VERSION 5.7 ;
  NOWIREEXTENSIONATPIN ON ;
  DIVIDERCHAR "/" ;
  BUSBITCHARS "[]" ;
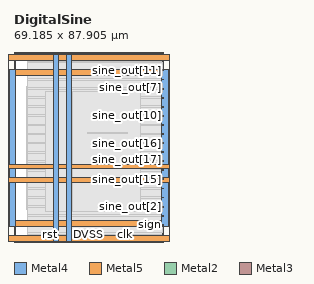
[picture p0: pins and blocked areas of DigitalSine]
MACRO DigitalSine
  CLASS BLOCK ;
  FOREIGN DigitalSine ;
  ORIGIN 0.000 0.000 ;
  SIZE 69.185 BY 87.905 ;
  PIN DVDD
    DIRECTION INOUT ;
    USE POWER ;
    PORT
      LAYER Metal4 ;
        RECT -2.240 7.120 0.760 79.820 ;
    END
    PORT
      LAYER Metal4 ;
        RECT 68.360 7.120 71.360 79.820 ;
    END
    PORT
      LAYER Metal5 ;
        RECT -2.240 7.120 71.360 10.120 ;
    END
    PORT
      LAYER Metal5 ;
        RECT -2.240 76.820 71.360 79.820 ;
    END
    PORT
      LAYER Metal4 ;
        RECT 18.260 0.120 20.460 86.820 ;
    END
    PORT
      LAYER Metal5 ;
        RECT -9.240 27.620 78.360 29.820 ;
    END
  END DVDD
  PIN DVSS
    DIRECTION INOUT ;
    USE GROUND ;
    PORT
      LAYER Metal4 ;
        RECT -9.240 0.120 -6.240 86.820 ;
    END
    PORT
      LAYER Metal4 ;
        RECT 75.360 0.120 78.360 86.820 ;
    END
    PORT
      LAYER Metal5 ;
        RECT -9.240 0.120 78.360 3.120 ;
    END
    PORT
      LAYER Metal5 ;
        RECT -9.240 83.820 78.360 86.820 ;
    END
    PORT
      LAYER Metal4 ;
        RECT 24.460 0.120 26.660 86.820 ;
    END
    PORT
      LAYER Metal5 ;
        RECT -9.240 33.820 78.360 36.020 ;
    END
  END DVSS
  PIN clk
    DIRECTION INPUT ;
    USE SIGNAL ;
    ANTENNAGATEAREA 1.450800 ;
    PORT
      LAYER Metal2 ;
        RECT 51.160 0.000 51.560 0.400 ;
    END
  END clk
  PIN rst
    DIRECTION INPUT ;
    USE SIGNAL ;
    ANTENNAGATEAREA 0.180700 ;
    PORT
      LAYER Metal2 ;
        RECT 16.600 0.000 17.000 0.400 ;
    END
  END rst
  PIN sign
    DIRECTION OUTPUT ;
    USE SIGNAL ;
    ANTENNADIFFAREA 0.708600 ;
    PORT
      LAYER Metal3 ;
        RECT 68.785 7.780 69.185 8.180 ;
    END
  END sign
  PIN signB
    DIRECTION OUTPUT ;
    USE SIGNAL ;
    ANTENNADIFFAREA 0.708600 ;
    PORT
      LAYER Metal3 ;
        RECT 68.785 3.580 69.185 3.980 ;
    END
  END signB
  PIN sine_out[0]
    DIRECTION OUTPUT ;
    USE SIGNAL ;
    ANTENNADIFFAREA 0.708600 ;
    PORT
      LAYER Metal3 ;
        RECT 68.785 11.980 69.185 12.380 ;
    END
  END sine_out[0]
  PIN sine_out[10]
    DIRECTION OUTPUT ;
    USE SIGNAL ;
    ANTENNADIFFAREA 0.708600 ;
    PORT
      LAYER Metal3 ;
        RECT 68.785 58.180 69.185 58.580 ;
    END
  END sine_out[10]
  PIN sine_out[11]
    DIRECTION OUTPUT ;
    USE SIGNAL ;
    ANTENNADIFFAREA 0.708600 ;
    PORT
      LAYER Metal3 ;
        RECT 68.785 79.180 69.185 79.580 ;
    END
  END sine_out[11]
  PIN sine_out[12]
    DIRECTION OUTPUT ;
    USE SIGNAL ;
    ANTENNADIFFAREA 0.708600 ;
    PORT
      LAYER Metal3 ;
        RECT 68.785 62.380 69.185 62.780 ;
    END
  END sine_out[12]
  PIN sine_out[13]
    DIRECTION OUTPUT ;
    USE SIGNAL ;
    ANTENNADIFFAREA 0.708600 ;
    PORT
      LAYER Metal3 ;
        RECT 68.785 70.780 69.185 71.180 ;
    END
  END sine_out[13]
  PIN sine_out[14]
    DIRECTION OUTPUT ;
    USE SIGNAL ;
    ANTENNADIFFAREA 0.708600 ;
    PORT
      LAYER Metal3 ;
        RECT 68.785 53.980 69.185 54.380 ;
    END
  END sine_out[14]
  PIN sine_out[15]
    DIRECTION OUTPUT ;
    USE SIGNAL ;
    ANTENNADIFFAREA 0.708600 ;
    PORT
      LAYER Metal3 ;
        RECT 68.785 28.780 69.185 29.180 ;
    END
  END sine_out[15]
  PIN sine_out[16]
    DIRECTION OUTPUT ;
    USE SIGNAL ;
    ANTENNADIFFAREA 0.708600 ;
    PORT
      LAYER Metal3 ;
        RECT 68.785 45.580 69.185 45.980 ;
    END
  END sine_out[16]
  PIN sine_out[17]
    DIRECTION OUTPUT ;
    USE SIGNAL ;
    ANTENNADIFFAREA 0.708600 ;
    PORT
      LAYER Metal3 ;
        RECT 68.785 41.380 69.185 41.780 ;
    END
  END sine_out[17]
  PIN sine_out[1]
    DIRECTION OUTPUT ;
    USE SIGNAL ;
    ANTENNADIFFAREA 0.708600 ;
    PORT
      LAYER Metal3 ;
        RECT 68.785 20.380 69.185 20.780 ;
    END
  END sine_out[1]
  PIN sine_out[2]
    DIRECTION OUTPUT ;
    USE SIGNAL ;
    ANTENNADIFFAREA 0.708600 ;
    PORT
      LAYER Metal3 ;
        RECT 68.785 16.180 69.185 16.580 ;
    END
  END sine_out[2]
  PIN sine_out[3]
    DIRECTION OUTPUT ;
    USE SIGNAL ;
    ANTENNADIFFAREA 0.708600 ;
    PORT
      LAYER Metal3 ;
        RECT 68.785 37.180 69.185 37.580 ;
    END
  END sine_out[3]
  PIN sine_out[4]
    DIRECTION OUTPUT ;
    USE SIGNAL ;
    ANTENNADIFFAREA 0.708600 ;
    PORT
      LAYER Metal3 ;
        RECT 68.785 24.580 69.185 24.980 ;
    END
  END sine_out[4]
  PIN sine_out[5]
    DIRECTION OUTPUT ;
    USE SIGNAL ;
    ANTENNADIFFAREA 0.708600 ;
    PORT
      LAYER Metal3 ;
        RECT 68.785 49.780 69.185 50.180 ;
    END
  END sine_out[5]
  PIN sine_out[6]
    DIRECTION OUTPUT ;
    USE SIGNAL ;
    ANTENNADIFFAREA 0.708600 ;
    PORT
      LAYER Metal3 ;
        RECT 68.785 32.980 69.185 33.380 ;
    END
  END sine_out[6]
  PIN sine_out[7]
    DIRECTION OUTPUT ;
    USE SIGNAL ;
    ANTENNADIFFAREA 0.708600 ;
    PORT
      LAYER Metal3 ;
        RECT 68.785 74.980 69.185 75.380 ;
    END
  END sine_out[7]
  PIN sine_out[8]
    DIRECTION OUTPUT ;
    USE SIGNAL ;
    ANTENNADIFFAREA 0.708600 ;
    PORT
      LAYER Metal3 ;
        RECT 68.785 66.580 69.185 66.980 ;
    END
  END sine_out[8]
  PIN sine_out[9]
    DIRECTION OUTPUT ;
    USE SIGNAL ;
    ANTENNADIFFAREA 0.708600 ;
    PORT
      LAYER Metal3 ;
        RECT 68.785 83.380 69.185 83.780 ;
    END
  END sine_out[9]
  OBS
      LAYER GatPoly ;
        RECT 5.760 14.970 63.360 71.970 ;
      LAYER Metal1 ;
        RECT 5.760 14.900 63.360 72.040 ;
      LAYER Metal2 ;
        RECT 6.135 0.610 64.425 83.725 ;
        RECT 6.135 0.400 16.390 0.610 ;
        RECT 17.210 0.400 50.950 0.610 ;
        RECT 51.770 0.400 64.425 0.610 ;
      LAYER Metal3 ;
        RECT 6.095 83.170 68.575 83.680 ;
        RECT 6.095 79.790 68.785 83.170 ;
        RECT 6.095 78.970 68.575 79.790 ;
        RECT 6.095 75.590 68.785 78.970 ;
        RECT 6.095 74.770 68.575 75.590 ;
        RECT 6.095 71.390 68.785 74.770 ;
        RECT 6.095 70.570 68.575 71.390 ;
        RECT 6.095 67.190 68.785 70.570 ;
        RECT 6.095 66.370 68.575 67.190 ;
        RECT 6.095 62.990 68.785 66.370 ;
        RECT 6.095 62.170 68.575 62.990 ;
        RECT 6.095 58.790 68.785 62.170 ;
        RECT 6.095 57.970 68.575 58.790 ;
        RECT 6.095 54.590 68.785 57.970 ;
        RECT 6.095 53.770 68.575 54.590 ;
        RECT 6.095 50.390 68.785 53.770 ;
        RECT 6.095 49.570 68.575 50.390 ;
        RECT 6.095 46.190 68.785 49.570 ;
        RECT 6.095 45.370 68.575 46.190 ;
        RECT 6.095 41.990 68.785 45.370 ;
        RECT 6.095 41.170 68.575 41.990 ;
        RECT 6.095 37.790 68.785 41.170 ;
        RECT 6.095 36.970 68.575 37.790 ;
        RECT 6.095 33.590 68.785 36.970 ;
        RECT 6.095 32.770 68.575 33.590 ;
        RECT 6.095 29.390 68.785 32.770 ;
        RECT 6.095 28.570 68.575 29.390 ;
        RECT 6.095 25.190 68.785 28.570 ;
        RECT 6.095 24.370 68.575 25.190 ;
        RECT 6.095 20.990 68.785 24.370 ;
        RECT 6.095 20.170 68.575 20.990 ;
        RECT 6.095 16.790 68.785 20.170 ;
        RECT 6.095 15.970 68.575 16.790 ;
        RECT 6.095 12.590 68.785 15.970 ;
        RECT 6.095 11.770 68.575 12.590 ;
        RECT 6.095 8.390 68.785 11.770 ;
        RECT 6.095 7.570 68.575 8.390 ;
        RECT 6.095 4.190 68.785 7.570 ;
        RECT 6.095 3.680 68.575 4.190 ;
      LAYER Metal4 ;
        RECT 14.780 14.135 18.050 69.445 ;
        RECT 20.670 14.135 24.250 69.445 ;
        RECT 26.870 14.135 58.660 69.445 ;
      LAYER Metal5 ;
        RECT 33.935 50.300 52.465 50.500 ;
  END
END DigitalSine
END LIBRARY

